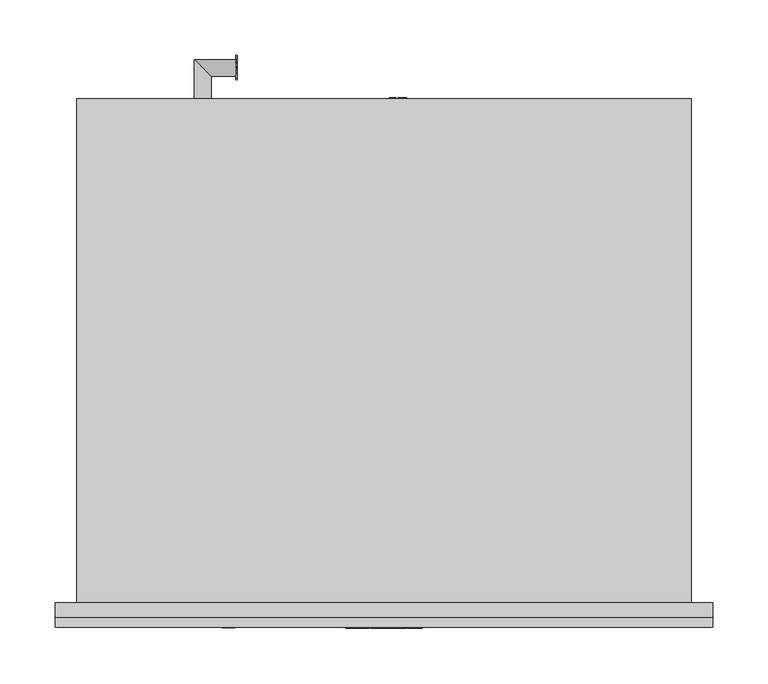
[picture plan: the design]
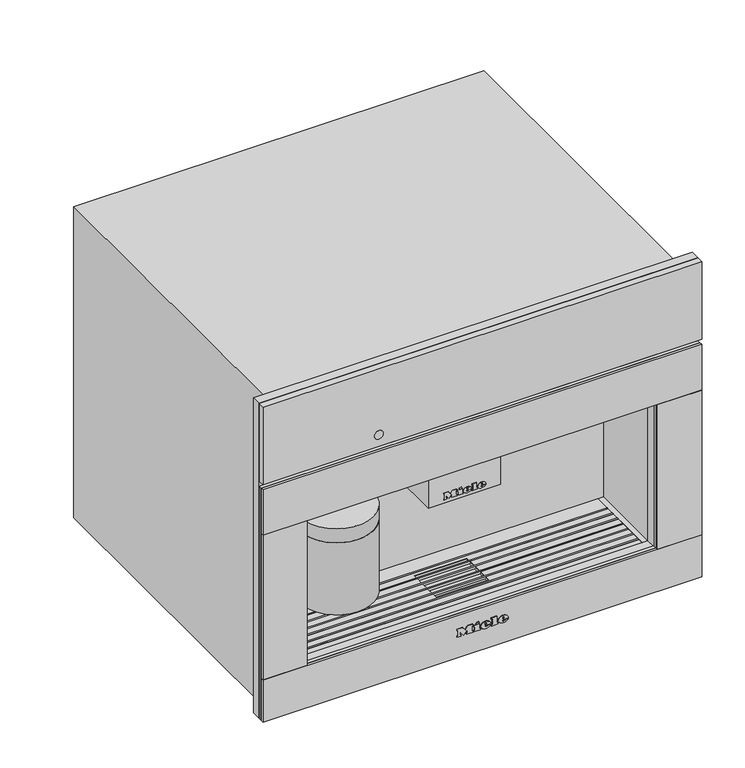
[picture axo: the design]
"""IFC4 building model written with IfcOpenShell, lengths in millimetres: proxy geometry."""

from ifc_helpers import new_model, si_unit, point, frame, frame_2d, origin, place, context, project, spatial, polyline, circle_curve, ellipse_curve, trimmed, segment, composite_curve, outline, extrude, faceted_brep, source, transform, mapped, element, save
from ifc_brep_helpers import plane_surface, cylinder_surface, revolved_surface, extruded_surface, advanced_brep


def specialty_equipment_e3dbea78(model_context):
    return source(origin(), model_context, "Body", "SolidModel", [
        extrude(outline(composite_curve([segment(trimmed(circle_curve(frame_2d((-14.0, 36.5)), 5.0), [point((-9.0, 36.5))], [point((-19.0, 36.5))], False, "CARTESIAN"), True, "CONTINUOUS"), segment(trimmed(circle_curve(frame_2d((-14.0, 36.5)), 5.0), [point((-19.0, 36.5))], [point((-9.0, 36.5))], False, "CARTESIAN"), True, "CONTINUOUS")], self_intersect=False)), frame((0.0, 0.0, 193.0), z_axis=(0.0, 0.0, 1.0), x_axis=(1.0, 0.0, 0.0)), (0.0, 0.0, 1.0), 5.0),
        extrude(outline(composite_curve([segment(trimmed(circle_curve(frame_2d((14.0, 36.5)), 5.0), [point((19.0, 36.5))], [point((9.0, 36.5))], False, "CARTESIAN"), True, "CONTINUOUS"), segment(trimmed(circle_curve(frame_2d((14.0, 36.5)), 5.0), [point((9.0, 36.5))], [point((19.0, 36.5))], False, "CARTESIAN"), True, "CONTINUOUS")], self_intersect=False)), frame((0.0, 0.0, 193.0), z_axis=(0.0, 0.0, 1.0), x_axis=(1.0, 0.0, 0.0)), (0.0, 0.0, 1.0), 5.0),
        extrude(outline(composite_curve([segment(trimmed(circle_curve(frame_2d((-156.5, 49.5)), 50.0), [point((-106.5, 49.5))], [point((-206.5, 49.5))], False, "CARTESIAN"), True, "CONTINUOUS"), segment(trimmed(circle_curve(frame_2d((-156.5, 49.5)), 50.0), [point((-206.5, 49.5))], [point((-106.5, 49.5))], False, "CARTESIAN"), True, "CONTINUOUS")], self_intersect=False)), frame((0.0, 0.0, 100.0), z_axis=(0.0, 0.0, 1.0), x_axis=(1.0, 0.0, 0.0)), (0.0, 0.0, 1.0), 103.0),
        extrude(outline(polyline([(-49.0, 95.0), (49.0, 95.0), (49.0, 20.0), (-49.0, 20.0), (-49.0, 95.0)])), frame((0.0, 0.0, 198.0), z_axis=(0.0, 0.0, 1.0), x_axis=(1.0, 0.0, 0.0)), (0.0, 0.0, 1.0), 75.0),
        extrude(outline(polyline([(455.5, 297.5), (455.5, -297.5), (4.0, -297.5), (4.0, 297.5), (455.5, 297.5)]), holes=[polyline([(273.0, 237.5), (63.0, 237.5), (63.0, -237.5), (273.0, -237.5), (273.0, 237.5)])]), frame((0.0, -13.0, 0.0), z_axis=(0.0, 1.0, 0.0), x_axis=(0.0, 0.0, 1.0)), (0.0, 0.0, 1.0), 13.0),
        extrude(outline(polyline([(473.48348, 22.0), (473.48348, 32.045631), (474.7391839, 32.045631), (474.7391839, 27.128275), (479.8895318, 32.045631), (481.6455552, 32.045631), (477.319263, 27.9155425), (481.8025182, 22.0), (480.267224, 22.0), (476.4289885, 27.0669613), (474.7391839, 25.4531857), (474.7391839, 22.0), (473.48348, 22.0)])), frame((-134.0, 0.0, 0.0), z_axis=(1.0, 0.0, 0.0), x_axis=(0.0, 1.0, 0.0)), (0.0, 0.0, 1.0), 1.0),
        extrude(outline(polyline([(484.5420128, 22.0), (481.8025182, 32.045631), (483.0974628, 32.045631), (484.6867131, 25.4433755), (485.1772224, 23.4053092), (485.7020674, 25.207931), (487.6935352, 32.045631), (489.5599232, 32.045631), (491.0069257, 27.0890343), (492.0835937, 23.4053092), (492.5593878, 25.3845144), (494.1609007, 32.045631), (495.4582979, 32.045631), (492.7212558, 22.0), (491.3772603, 22.0), (488.9664069, 29.7500474), (488.630408, 30.8316204), (488.2527159, 29.5293182), (486.0576866, 22.0), (484.5420128, 22.0)])), frame((-134.0, 0.0, 0.0), z_axis=(1.0, 0.0, 0.0), x_axis=(0.0, 1.0, 0.0)), (0.0, 0.0, 1.0), 1.0),
        advanced_brep(
        [(-156.5, 456.0, 27.0), (-171.5, 456.0, 27.0), (-156.5, 476.5, 27.0), (-171.5, 491.5, 27.0), (-134.0, 476.5, 27.0), (-134.0, 491.5, 27.0)],
        [
            (0, 1, circle_curve(frame((-164.0, 456.0, 27.0), z_axis=(0.0, -1.0, 0.0), x_axis=(-1.0, 0.0, 0.0)), 7.5)),
            (1, 0, circle_curve(frame((-164.0, 456.0, 27.0), z_axis=(0.0, -1.0, 0.0), x_axis=(-1.0, 0.0, 0.0)), 7.5)),
            (0, 2),
            (2, 3, ellipse_curve(frame((-164.0, 484.0, 27.0), z_axis=(-0.707106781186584, -0.7071067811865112, 0.0), x_axis=(0.7071067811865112, -0.7071067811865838, 0.0)), 10.6066017, 7.5)),
            (3, 1),
            (3, 2, ellipse_curve(frame((-164.0, 484.0, 27.0), z_axis=(-0.707106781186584, -0.7071067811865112, 0.0), x_axis=(0.7071067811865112, -0.7071067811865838, 0.0)), 10.6066017, 7.5)),
            (4, 5, circle_curve(frame((-134.0, 484.0, 27.0), z_axis=(1.0, 0.0, 0.0), x_axis=(0.0, 1.0, 0.0)), 7.5)),
            (5, 4, circle_curve(frame((-134.0, 484.0, 27.0), z_axis=(1.0, 0.0, 0.0), x_axis=(0.0, 1.0, 0.0)), 7.5)),
            (2, 4),
            (5, 3),
        ],
        [
            plane_surface(frame((-164.0, 456.0, 27.0), z_axis=(0.0, -1.0, 0.0), x_axis=(0.0, 0.0, 1.0))),
            cylinder_surface(frame((-164.0, 456.0, 27.0), z_axis=(0.0, -1.0, 0.0), x_axis=(-1.0, 0.0, 0.0)), 7.5),
            plane_surface(frame((-134.0, 484.0, 27.0), z_axis=(1.0, 0.0, 0.0), x_axis=(0.0, 0.0, 1.0))),
            cylinder_surface(frame((-164.0, 484.0, 27.0), z_axis=(-1.0, 0.0, 0.0), x_axis=(0.0, 1.0, 0.0)), 7.5),
        ],
        [
            (0, [[1, 2]]),
            (1, [[-1, 3, 4, 5]]),
            (1, [[-2, -5, 6, -3]]),
            (2, [[7, 8]]),
            (3, [[-4, 9, -8, 10]]),
            (3, [[-6, -10, -7, -9]]),
        ],
    ),
        extrude(outline(polyline([(97.0, 20.4012141), (107.045631, 20.4012141), (107.045631, 13.1809168), (105.7899271, 13.1809168), (105.7899271, 19.1455102), (102.8076304, 19.1455102), (102.8076304, 13.4948427), (101.5519266, 13.4948427), (101.5519266, 19.1455102), (98.2557039, 19.1455102), (98.2557039, 13.0239538), (97.0, 13.0239538), (97.0, 20.4012141)])), frame((0.0, 456.0, 0.0), z_axis=(0.0, 1.0, 0.0), x_axis=(0.0, 0.0, 1.0)), (0.0, 0.0, 1.0), 1.0),
        extrude(outline(polyline([(97.0, 11.140398), (107.045631, 11.140398), (107.045631, 9.8846941), (98.2557039, 9.8846941), (98.2557039, 4.8618786), (97.0, 4.8618786), (97.0, 11.140398)])), frame((0.0, 456.0, 0.0), z_axis=(0.0, 1.0, 0.0), x_axis=(0.0, 0.0, 1.0)), (0.0, 0.0, 1.0), 1.0),
        advanced_brep(
        [(55.0, 425.5, 102.0), (55.0, 410.5, 102.0), (20.5239538, 425.5, 102.0), (5.5239538, 410.5, 102.0), (20.5239538, 456.0, 102.0), (5.5239538, 456.0, 102.0)],
        [
            (0, 1, circle_curve(frame((55.0, 418.0, 102.0), z_axis=(1.0, 0.0, 0.0), x_axis=(0.0, -1.0, 0.0)), 7.5)),
            (1, 0, circle_curve(frame((55.0, 418.0, 102.0), z_axis=(1.0, 0.0, 0.0), x_axis=(0.0, -1.0, 0.0)), 7.5)),
            (0, 2),
            (2, 3, ellipse_curve(frame((13.0239538, 418.0, 102.0), z_axis=(0.7071067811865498, -0.7071067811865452, 0.0), x_axis=(0.7071067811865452, 0.7071067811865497, 0.0)), 10.6066017, 7.5)),
            (3, 1),
            (3, 2, ellipse_curve(frame((13.0239538, 418.0, 102.0), z_axis=(0.7071067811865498, -0.7071067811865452, 0.0), x_axis=(0.7071067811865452, 0.7071067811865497, 0.0)), 10.6066017, 7.5)),
            (4, 5, circle_curve(frame((13.0239538, 456.0, 102.0), z_axis=(0.0, 1.0, 0.0), x_axis=(-1.0, 0.0, 0.0)), 7.5)),
            (5, 4, circle_curve(frame((13.0239538, 456.0, 102.0), z_axis=(0.0, 1.0, 0.0), x_axis=(-1.0, 0.0, 0.0)), 7.5)),
            (2, 4),
            (5, 3),
        ],
        [
            plane_surface(frame((55.0, 418.0, 102.0), z_axis=(1.0, 0.0, 0.0), x_axis=(0.0, 0.0, 1.0))),
            cylinder_surface(frame((55.0, 418.0, 102.0), z_axis=(1.0, 0.0, 0.0), x_axis=(0.0, -1.0, 0.0)), 7.5),
            plane_surface(frame((13.0239538, 456.0, 102.0), z_axis=(0.0, 1.0, 0.0), x_axis=(0.0, 0.0, 1.0))),
            cylinder_surface(frame((13.0239538, 418.0, 102.0), z_axis=(0.0, -1.0, 0.0), x_axis=(-1.0, 0.0, 0.0)), 7.5),
        ],
        [
            (0, [[1, 2]]),
            (1, [[-1, 3, 4, 5]]),
            (1, [[-2, -5, 6, -3]]),
            (2, [[7, 8]]),
            (3, [[-4, 9, -8, 10]]),
            (3, [[-6, -10, -7, -9]]),
        ],
    ),
        advanced_brep(
        [(-110.0, 49.5, 252.0), (-203.0, 49.5, 252.0), (-206.5, 49.5, 223.5), (-106.5, 49.5, 223.5), (-110.0, 49.5, 273.0), (-203.0, 49.5, 273.0), (-156.5, 49.5, 273.0), (-106.5, 49.5, 203.0), (-206.5, 49.5, 203.0), (-156.5, 49.5, 203.0)],
        [
            (0, 1, circle_curve(frame((-156.5, 49.5, 252.0), z_axis=(0.0, 0.0, -1.0), x_axis=(-1.0, 0.0, 0.0)), 46.5)),
            (1, 2, circle_curve(frame((-206.7961166, 49.5, 238.0012775), z_axis=(0.0, 1.0, 0.0), x_axis=(-1.0, 0.0, 0.0)), 14.5043005)),
            (2, 3, circle_curve(frame((-156.5, 49.5, 223.5), z_axis=(0.0, 0.0, 1.0), x_axis=(-1.0, 0.0, 0.0)), 50.0)),
            (3, 0, circle_curve(frame((-106.2038834, 49.5, 238.0012775), z_axis=(0.0, 1.0, 0.0), x_axis=(1.0, 0.0, 0.0)), 14.5043005)),
            (4, 5, circle_curve(frame((-156.5, 49.5, 273.0), z_axis=(0.0, 0.0, -1.0), x_axis=(-1.0, 0.0, 0.0)), 46.5)),
            (5, 1),
            (0, 4),
            (6, 4),
            (4, 5, circle_curve(frame((-156.5, 49.5, 273.0), z_axis=(0.0, 0.0, 1.0), x_axis=(-1.0, 0.0, 0.0)), 46.5)),
            (5, 6),
            (7, 8, circle_curve(frame((-156.5, 49.5, 203.0), z_axis=(0.0, 0.0, -1.0), x_axis=(-1.0, 0.0, 0.0)), 50.0)),
            (8, 9),
            (9, 7),
            (8, 7, circle_curve(frame((-156.5, 49.5, 203.0), z_axis=(0.0, 0.0, -1.0), x_axis=(-1.0, 0.0, 0.0)), 50.0)),
            (2, 8),
            (7, 3),
            (2, 3, circle_curve(frame((-156.5, 49.5, 223.5), z_axis=(0.0, 0.0, -1.0), x_axis=(-1.0, 0.0, 0.0)), 50.0)),
            (1, 0, circle_curve(frame((-156.5, 49.5, 252.0), z_axis=(0.0, 0.0, -1.0), x_axis=(-1.0, 0.0, 0.0)), 46.5)),
        ],
        [
            revolved_surface(trimmed(ellipse_curve(frame((-206.7961166, 49.5, 238.0012775), z_axis=(0.0, -1.0, 0.0), x_axis=(-1.0, 0.0, 0.0)), 14.5043005, 14.5043005), [point((-206.5, 49.5, 223.5))], [point((-203.0, 49.5, 252.0))], True, "CARTESIAN"), (-156.5, 49.5, 388.7361736), (0.0, 0.0, 1.0)),
            cylinder_surface(frame((-156.5, 49.5, 388.7361736), z_axis=(0.0, 0.0, 1.0), x_axis=(-1.0, 0.0, 0.0)), 46.5),
            plane_surface(frame((-156.5, 49.5, 273.0), z_axis=(0.0, 0.0, 1.0), x_axis=(-1.0, 0.0, 0.0))),
            plane_surface(frame((-156.5, 49.5, 203.0), z_axis=(0.0, 0.0, -1.0), x_axis=(-1.0, 0.0, 0.0))),
            cylinder_surface(frame((-156.5, 49.5, 388.7361736), z_axis=(0.0, 0.0, 1.0), x_axis=(-1.0, 0.0, 0.0)), 50.0),
        ],
        [
            (0, [[1, 2, 3, 4]]),
            (1, [[5, 6, -1, 7]]),
            (2, [[8, 9, 10]]),
            (3, [[11, 12, 13]]),
            (3, [[14, -13, -12]]),
            (4, [[-3, 15, -11, 16]]),
            (4, [[17, -16, -14, -15]]),
            (0, [[18, -4, -17, -2]]),
            (1, [[-9, -7, -18, -6]]),
            (2, [[-10, -5, -8]]),
        ],
    ),
        faceted_brep([(229.5, 82.0925571, 60.0), (229.5, 80.0925571, 60.0), (-229.5, 80.0925571, 60.0), (-229.5, 82.0925571, 60.0), (229.5, 70.0550731, 60.0), (229.5, 68.0550731, 60.0), (-229.5, 68.0550731, 60.0), (-229.5, 70.0550731, 60.0), (229.5, 58.0175891, 60.0), (229.5, 56.0175891, 60.0), (-229.5, 56.0175891, 60.0), (-229.5, 58.0175891, 60.0), (229.5, 45.9801052, 60.0), (229.5, 43.9801052, 60.0), (-229.5, 43.9801052, 60.0), (-229.5, 45.9801052, 60.0), (229.5, 33.9426212, 60.0), (229.5, 31.9426212, 60.0), (-229.5, 31.9426212, 60.0), (-229.5, 33.9426212, 60.0), (229.5, 21.9776522, 60.0), (229.5, 19.9776522, 60.0), (-229.5, 19.9776522, 60.0), (-229.5, 21.9776522, 60.0), (229.5, 10.0, 60.0), (229.5, 8.0, 60.0), (-229.5, 8.0, 60.0), (-229.5, 10.0, 60.0), (-229.5, 45.9801052, 62.0), (-36.0, 45.9801052, 62.0), (-36.0, 45.9801052, 63.0), (-229.5, 45.9801052, 63.0), (-229.5, 45.9801052, 63.5), (229.5, 45.9801052, 63.5), (229.5, 45.9801052, 63.0), (36.0, 45.9801052, 63.0), (36.0, 45.9801052, 62.0), (229.5, 45.9801052, 62.0), (229.5, 19.9776522, 62.0), (229.5, 10.0, 62.0), (-229.5, 10.0, 62.0), (-229.5, 19.9776522, 62.0), (229.5, 43.9801052, 62.0), (229.5, 33.9426212, 62.0), (36.0, 33.9426212, 62.0), (36.0, 43.9801052, 62.0), (229.5, 56.0175891, 62.0), (36.0, 56.0175891, 62.0), (229.5, 68.0550731, 62.0), (229.5, 58.0175891, 62.0), (36.0, 58.0175891, 62.0), (36.0, 68.0550731, 62.0), (-229.5, 33.9426212, 62.0), (-229.5, 43.9801052, 62.0), (-36.0, 43.9801052, 62.0), (-36.0, 33.9426212, 62.0), (-229.5, 56.0175891, 62.0), (-36.0, 56.0175891, 62.0), (-229.5, 58.0175891, 62.0), (-229.5, 68.0550731, 62.0), (-36.0, 68.0550731, 62.0), (-36.0, 58.0175891, 62.0), (-229.5, 104.5, 62.0), (229.5, 104.5, 62.0), (229.5, 82.0925571, 62.0), (-229.5, 82.0925571, 62.0), (36.0, 76.0, 62.0), (-36.0, 76.0, 62.0), (-36.0, 70.0550731, 62.0), (-229.5, 70.0550731, 62.0), (-229.5, 80.0925571, 62.0), (229.5, 80.0925571, 62.0), (229.5, 70.0550731, 62.0), (36.0, 70.0550731, 62.0), (229.5, 0.0, 62.0), (-229.5, 0.0, 62.0), (-229.5, 8.0, 62.0), (229.5, 8.0, 62.0), (-36.0, 25.0, 62.0), (36.0, 25.0, 62.0), (36.0, 31.9426212, 62.0), (229.5, 31.9426212, 62.0), (229.5, 21.9776522, 62.0), (-229.5, 21.9776522, 62.0), (-229.5, 31.9426212, 62.0), (-36.0, 31.9426212, 62.0), (229.5, 104.5, 63.0), (-229.5, 104.5, 63.0), (-229.5, 82.0925571, 63.0), (229.5, 82.0925571, 63.0), (-229.5, 0.0, 63.0), (229.5, 0.0, 63.0), (229.5, 8.0, 63.0), (-229.5, 8.0, 63.0), (-36.0, 76.0, 63.0), (36.0, 76.0, 63.0), (36.0, 70.0550731, 63.0), (229.5, 70.0550731, 63.0), (229.5, 80.0925571, 63.0), (-229.5, 80.0925571, 63.0), (-229.5, 70.0550731, 63.0), (-36.0, 70.0550731, 63.0), (36.0, 25.0, 63.0), (-36.0, 25.0, 63.0), (-36.0, 31.9426212, 63.0), (-229.5, 31.9426212, 63.0), (-229.5, 21.9776522, 63.0), (229.5, 21.9776522, 63.0), (229.5, 31.9426212, 63.0), (36.0, 31.9426212, 63.0), (-229.5, 19.9776522, 63.0), (-229.5, 10.0, 63.0), (229.5, 10.0, 63.0), (229.5, 19.9776522, 63.0), (-229.5, 43.9801052, 63.0), (-229.5, 33.9426212, 63.0), (-36.0, 33.9426212, 63.0), (-36.0, 43.9801052, 63.0), (-229.5, 56.0175891, 63.0), (-36.0, 56.0175891, 63.0), (-229.5, 68.0550731, 63.0), (-229.5, 58.0175891, 63.0), (-36.0, 58.0175891, 63.0), (-36.0, 68.0550731, 63.0), (229.5, 33.9426212, 63.0), (229.5, 43.9801052, 63.0), (36.0, 43.9801052, 63.0), (36.0, 33.9426212, 63.0), (229.5, 56.0175891, 63.0), (36.0, 56.0175891, 63.0), (229.5, 58.0175891, 63.0), (229.5, 68.0550731, 63.0), (36.0, 68.0550731, 63.0), (36.0, 58.0175891, 63.0), (-229.5, 8.0, 63.5), (-229.5, 10.0, 63.5), (-229.5, 19.9776522, 63.5), (-229.5, 21.9776522, 63.5), (-229.5, 31.9426212, 63.5), (-229.5, 33.9426212, 63.5), (-229.5, 43.9801052, 63.5), (-229.5, 56.0175891, 63.5), (-229.5, 58.0175891, 63.5), (-229.5, 68.0550731, 63.5), (-229.5, 70.0550731, 63.5), (-229.5, 80.0925571, 63.5), (-229.5, 82.0925571, 63.5), (229.5, 82.0925571, 63.5), (229.5, 80.0925571, 63.5), (229.5, 70.0550731, 63.5), (229.5, 68.0550731, 63.5), (229.5, 58.0175891, 63.5), (229.5, 56.0175891, 63.5), (229.5, 43.9801052, 63.5), (229.5, 33.9426212, 63.5), (229.5, 31.9426212, 63.5), (229.5, 21.9776522, 63.5), (229.5, 19.9776522, 63.5), (229.5, 10.0, 63.5), (229.5, 8.0, 63.5)], [[[0, 1, 2, 3]], [[4, 5, 6, 7]], [[8, 9, 10, 11]], [[12, 13, 14, 15]], [[16, 17, 18, 19]], [[20, 21, 22, 23]], [[24, 25, 26, 27]], [[12, 15, 28, 29, 30, 31, 32, 33, 34, 35, 36, 37]], [[38, 39, 40, 41]], [[42, 43, 44, 45]], [[46, 37, 36, 47]], [[48, 49, 50, 51]], [[52, 53, 54, 55]], [[28, 56, 57, 29]], [[58, 59, 60, 61]], [[62, 63, 64, 65]], [[66, 67, 68, 69, 70, 71, 72, 73]], [[74, 75, 76, 77]], [[78, 79, 80, 81, 82, 83, 84, 85]], [[86, 87, 88, 89]], [[90, 91, 92, 93]], [[94, 95, 96, 97, 98, 99, 100, 101]], [[102, 103, 104, 105, 106, 107, 108, 109]], [[110, 111, 112, 113]], [[114, 115, 116, 117]], [[118, 31, 30, 119]], [[120, 121, 122, 123]], [[124, 125, 126, 127]], [[34, 128, 129, 35]], [[130, 131, 132, 133]], [[63, 62, 87, 86]], [[87, 62, 65, 3, 2, 70, 69, 7, 6, 59, 58, 11, 10, 56, 28, 15, 14, 53, 52, 19, 18, 84, 83, 23, 22, 41, 40, 27, 26, 76, 75, 90, 93, 134, 135, 111, 110, 136, 137, 106, 105, 138, 139, 115, 114, 140, 32, 31, 118, 141, 142, 121, 120, 143, 144, 100, 99, 145, 146, 88]], [[75, 74, 91, 90]], [[63, 86, 89, 147, 148, 98, 97, 149, 150, 131, 130, 151, 152, 128, 34, 33, 153, 125, 124, 154, 155, 108, 107, 156, 157, 113, 112, 158, 159, 92, 91, 74, 77, 25, 24, 39, 38, 21, 20, 82, 81, 17, 16, 43, 42, 13, 12, 37, 46, 9, 8, 49, 48, 5, 4, 72, 71, 1, 0, 64]], [[66, 95, 94, 67]], [[55, 54, 117, 116]], [[29, 57, 119, 30]], [[61, 60, 123, 122]], [[67, 94, 101, 68]], [[103, 78, 85, 104]], [[78, 103, 102, 79]], [[45, 44, 127, 126]], [[47, 36, 35, 129]], [[51, 50, 133, 132]], [[95, 66, 73, 96]], [[79, 102, 109, 80]], [[158, 135, 134, 159]], [[156, 137, 136, 157]], [[154, 139, 138, 155]], [[33, 32, 140, 153]], [[151, 142, 141, 152]], [[149, 144, 143, 150]], [[147, 146, 145, 148]], [[24, 27, 40, 39]], [[135, 158, 112, 111]], [[26, 25, 77, 76]], [[159, 134, 93, 92]], [[20, 23, 83, 82]], [[137, 156, 107, 106]], [[22, 21, 38, 41]], [[157, 136, 110, 113]], [[16, 19, 52, 55, 116, 115, 139, 154, 124, 127, 44, 43]], [[18, 17, 81, 80, 109, 108, 155, 138, 105, 104, 85, 84]], [[14, 13, 42, 45, 126, 125, 153, 140, 114, 117, 54, 53]], [[8, 11, 58, 61, 122, 121, 142, 151, 130, 133, 50, 49]], [[10, 9, 46, 47, 129, 128, 152, 141, 118, 119, 57, 56]], [[4, 7, 69, 68, 101, 100, 144, 149, 97, 96, 73, 72]], [[6, 5, 48, 51, 132, 131, 150, 143, 120, 123, 60, 59]], [[0, 3, 65, 64]], [[146, 147, 89, 88]], [[2, 1, 71, 70]], [[148, 145, 99, 98]]]),
        faceted_brep([(-278.0, 456.0, 0.0), (-278.0, 0.0, 0.0), (-278.0, 0.0, 446.0), (-278.0, 456.0, 446.0), (278.0, 456.0, 0.0), (278.0, 456.0, 446.0), (278.0, 0.0, 446.0), (278.0, 0.0, 0.0), (55.0, 456.0, 133.0), (-22.0, 456.0, 133.0), (-22.0, 456.0, 89.0), (35.0, 456.0, 66.0), (55.0, 456.0, 66.0), (-36.0, 76.0, 58.0), (36.0, 76.0, 58.0), (36.0, 76.0, 62.0), (-36.0, 76.0, 62.0), (36.0, 25.0, 58.0), (-36.0, 25.0, 58.0), (-36.0, 25.0, 62.0), (36.0, 25.0, 62.0), (237.5, 0.0, 273.0), (237.5, 0.0, 63.0), (229.5, 0.0, 63.0), (229.5, 0.0, 62.0), (-229.5, 0.0, 62.0), (-229.5, 0.0, 63.0), (-237.5, 0.0, 63.0), (-237.5, 0.0, 273.0), (237.5, 104.5, 273.0), (-237.5, 104.5, 273.0), (-237.5, 104.5, 63.0), (-229.5, 104.5, 63.0), (-229.5, 104.5, 62.0), (229.5, 104.5, 62.0), (229.5, 104.5, 63.0), (237.5, 104.5, 63.0), (-22.0, 400.0, 133.0), (55.0, 400.0, 133.0), (55.0, 400.0, 66.0), (35.0, 400.0, 66.0), (-22.0, 400.0, 89.0)], [[[0, 1, 2, 3]], [[4, 5, 6, 7]], [[0, 3, 5, 4], [8, 9, 10, 11, 12]], [[13, 14, 15, 16]], [[17, 18, 19, 20]], [[3, 2, 6, 5]], [[2, 1, 7, 6], [21, 22, 23, 24, 25, 26, 27, 28]], [[1, 0, 4, 7]], [[29, 30, 31, 32, 33, 34, 35, 36]], [[29, 36, 22, 21]], [[22, 36, 35, 23]], [[31, 27, 26, 32]], [[31, 30, 28, 27]], [[30, 29, 21, 28]], [[34, 33, 25, 24], [16, 15, 20, 19]], [[25, 33, 32, 26]], [[34, 24, 23, 35]], [[14, 13, 18, 17]], [[18, 13, 16, 19]], [[14, 17, 20, 15]], [[37, 38, 39, 40, 41]], [[38, 37, 9, 8]], [[39, 38, 8, 12]], [[40, 39, 12, 11]], [[41, 40, 11, 10]], [[37, 41, 10, 9]]]),
        advanced_brep(
        [(27.088, -23.0, 36.7018), (27.088, -23.0, 37.8532), (34.7146, -23.0, 37.8532), (21.445, -23.0, 37.8532), (24.58, -23.0, 34.0), (34.5208, -23.0, 36.7018), (31.078, -23.0, 36.7018), (28.3648, -23.0, 35.425), (27.088, -23.0, 39.3124), (27.088, -23.0, 40.555), (29.0374, -23.0, 40.555), (29.0374, -23.0, 39.3124), (27.088, -22.0, 36.7018), (28.3648, -22.0, 35.425), (31.078, -22.0, 36.7018), (34.5208, -22.0, 36.7018), (24.58, -22.0, 34.0), (21.445, -22.0, 37.8532), (34.7146, -22.0, 37.8532), (27.088, -22.0, 37.8532), (27.088, -22.0, 39.3124), (29.0374, -22.0, 39.3124), (29.0374, -22.0, 40.555), (27.088, -22.0, 40.555)],
        [
            (0, 1),
            (1, 2),
            (2, 3, ellipse_curve(frame((28.0798, -23.0, 37.8532), z_axis=(0.0, -1.0, 0.0), x_axis=(-1.0, 0.0, 0.0)), 6.6348, 5.4834)),
            (3, 4, circle_curve(frame((25.8568622, -23.0, 38.2408), z_axis=(0.0, -1.0, 0.0), x_axis=(0.0, 0.0, -1.0)), 4.4288556)),
            (4, 5, circle_curve(frame((27.9469808, -23.0, 41.2504), z_axis=(0.0, -1.0, 0.0), x_axis=(0.0, 0.0, -1.0)), 7.9940516)),
            (5, 6),
            (6, 7, circle_curve(frame((28.9220588, -23.0, 37.762), z_axis=(0.0, 1.0, 0.0), x_axis=(0.0, 0.0, -1.0)), 2.4025208)),
            (7, 0, circle_curve(frame((28.3648, -23.0, 36.7018), z_axis=(0.0, 1.0, 0.0), x_axis=(0.0, 0.0, -1.0)), 1.2768)),
            (8, 9),
            (9, 10, circle_curve(frame((28.0627, -23.0, 40.555), z_axis=(0.0, 1.0, 0.0), x_axis=(0.0, 0.0, -1.0)), 0.9747)),
            (10, 11),
            (11, 8),
            (12, 13, circle_curve(frame((28.3648, -22.0, 36.7018), z_axis=(0.0, -1.0, 0.0), x_axis=(0.0, 0.0, -1.0)), 1.2768)),
            (13, 14, circle_curve(frame((28.9220588, -22.0, 37.762), z_axis=(0.0, -1.0, 0.0), x_axis=(0.0, 0.0, -1.0)), 2.4025208)),
            (14, 15),
            (15, 16, circle_curve(frame((27.9469808, -22.0, 41.2504), z_axis=(0.0, 1.0, 0.0), x_axis=(0.0, 0.0, -1.0)), 7.9940516)),
            (16, 17, circle_curve(frame((25.8568622, -22.0, 38.2408), z_axis=(0.0, 1.0, 0.0), x_axis=(0.0, 0.0, -1.0)), 4.4288556)),
            (17, 18, ellipse_curve(frame((28.0798, -22.0, 37.8532), z_axis=(0.0, 1.0, 0.0), x_axis=(-1.0, 0.0, 0.0)), 6.6348, 5.4834)),
            (18, 19),
            (19, 12),
            (20, 21),
            (21, 22),
            (22, 23, circle_curve(frame((28.0627, -22.0, 40.555), z_axis=(0.0, -1.0, 0.0), x_axis=(0.0, 0.0, -1.0)), 0.9747)),
            (23, 20),
            (0, 12),
            (19, 1),
            (18, 2),
            (5, 15),
            (14, 6),
            (17, 3),
            (13, 7),
            (16, 4),
            (8, 20),
            (23, 9),
            (22, 10),
            (21, 11),
        ],
        [
            plane_surface(frame((27.088, -23.0, 37.8532), z_axis=(0.0, -1.0, 0.0), x_axis=(0.0, 0.0, 1.0))),
            plane_surface(frame((27.088, -22.0, 37.8532), z_axis=(0.0, 1.0, 0.0), x_axis=(0.0, 0.0, -1.0))),
            plane_surface(frame((27.088, -23.0, 36.7018), z_axis=(1.0, 0.0, 0.0), x_axis=(0.0, 1.0, 0.0))),
            plane_surface(frame((27.088, -23.0, 37.8532), z_axis=(0.0, 0.0, -1.0), x_axis=(0.0, 1.0, 0.0))),
            plane_surface(frame((34.5208, -23.0, 36.7018), z_axis=(0.0, 0.0, 1.0), x_axis=(0.0, 1.0, 0.0))),
            extruded_surface(trimmed(ellipse_curve(frame((28.0798, -21.0, 37.8532), z_axis=(0.0, -1.0, 0.0), x_axis=(-1.0, 0.0, 0.0)), 6.6348, 5.4834), [point((34.7146, -21.0, 37.8532))], [point((21.445, -21.0, 37.8532))], True, "CARTESIAN"), (0.0, -1.0, 0.0), 1.0),
            revolved_surface(polyline([(28.9220588, -22.0, 35.3594792), (28.9220588, -23.0, 35.3594792)]), (28.9220588, -22.0, 37.762), (0.0, 1.0, 0.0)),
            revolved_surface(polyline([(28.3648, -22.0, 35.425), (28.3648, -23.0, 35.425)]), (28.3648, -22.0, 36.7018), (0.0, 1.0, 0.0)),
            cylinder_surface(frame((25.8568622, -22.0, 38.2408), z_axis=(0.0, -1.0, 0.0), x_axis=(0.0, 0.0, -1.0)), 4.4288556),
            cylinder_surface(frame((27.9469808, -22.0, 41.2504), z_axis=(0.0, -1.0, 0.0), x_axis=(0.0, 0.0, -1.0)), 7.9940516),
            plane_surface(frame((27.088, -23.0, 39.3124), z_axis=(1.0, 0.0, 0.0), x_axis=(0.0, 1.0, 0.0))),
            revolved_surface(polyline([(28.0627, -22.0, 39.5803), (28.0627, -23.0, 39.5803)]), (28.0627, -22.0, 40.555), (0.0, 1.0, 0.0)),
            plane_surface(frame((29.0374, -23.0, 40.555), z_axis=(-1.0, 0.0, 0.0), x_axis=(0.0, 1.0, 0.0))),
            plane_surface(frame((29.0374, -23.0, 39.3124), z_axis=(0.0, 0.0, 1.0), x_axis=(0.0, 1.0, 0.0))),
        ],
        [
            (0, [[1, 2, 3, 4, 5, 6, 7, 8], [9, 10, 11, 12]]),
            (1, [[13, 14, 15, 16, 17, 18, 19, 20], [21, 22, 23, 24]]),
            (2, [[-1, 25, -20, 26]]),
            (3, [[-2, -26, -19, 27]]),
            (4, [[-6, 28, -15, 29]]),
            (5, [[-3, -27, -18, 30]]),
            (6, [[-7, -29, -14, 31]]),
            (7, [[-8, -31, -13, -25]]),
            (8, [[-4, -30, -17, 32]]),
            (9, [[-5, -32, -16, -28]]),
            (10, [[-9, 33, -24, 34]]),
            (11, [[-10, -34, -23, 35]]),
            (12, [[-11, -35, -22, 36]]),
            (13, [[-12, -36, -21, -33]]),
        ],
    ),
        advanced_brep(
        [(3.2962, -23.0, 36.7018), (3.2962, -23.0, 37.8532), (10.9228, -23.0, 37.8532), (-2.3468, -23.0, 37.8532), (0.7882, -23.0, 34.0), (10.729, -23.0, 36.7018), (7.2862, -23.0, 36.7018), (4.573, -23.0, 35.425), (3.2962, -23.0, 39.3124), (3.2962, -23.0, 40.555), (5.2456, -23.0, 40.555), (5.2456, -23.0, 39.3124), (3.2962, -22.0, 36.7018), (4.573, -22.0, 35.425), (7.2862, -22.0, 36.7018), (10.729, -22.0, 36.7018), (0.7882, -22.0, 34.0), (-2.3468, -22.0, 37.8532), (10.9228, -22.0, 37.8532), (3.2962, -22.0, 37.8532), (3.2962, -22.0, 39.3124), (5.2456, -22.0, 39.3124), (5.2456, -22.0, 40.555), (3.2962, -22.0, 40.555)],
        [
            (0, 1),
            (1, 2),
            (2, 3, ellipse_curve(frame((4.288, -23.0, 37.8532), z_axis=(0.0, -1.0, 0.0), x_axis=(-1.0, 0.0, 0.0)), 6.6348, 5.4834)),
            (3, 4, circle_curve(frame((2.0650622, -23.0, 38.2408), z_axis=(0.0, -1.0, 0.0), x_axis=(0.0, 0.0, -1.0)), 4.4288556)),
            (4, 5, circle_curve(frame((4.1551808, -23.0, 41.2504), z_axis=(0.0, -1.0, 0.0), x_axis=(0.0, 0.0, -1.0)), 7.9940516)),
            (5, 6),
            (6, 7, circle_curve(frame((5.1302588, -23.0, 37.762), z_axis=(0.0, 1.0, 0.0), x_axis=(0.0, 0.0, -1.0)), 2.4025208)),
            (7, 0, circle_curve(frame((4.573, -23.0, 36.7018), z_axis=(0.0, 1.0, 0.0), x_axis=(0.0, 0.0, -1.0)), 1.2768)),
            (8, 9),
            (9, 10, circle_curve(frame((4.2709, -23.0, 40.555), z_axis=(0.0, 1.0, 0.0), x_axis=(0.0, 0.0, -1.0)), 0.9747)),
            (10, 11),
            (11, 8),
            (12, 13, circle_curve(frame((4.573, -22.0, 36.7018), z_axis=(0.0, -1.0, 0.0), x_axis=(0.0, 0.0, -1.0)), 1.2768)),
            (13, 14, circle_curve(frame((5.1302588, -22.0, 37.762), z_axis=(0.0, -1.0, 0.0), x_axis=(0.0, 0.0, -1.0)), 2.4025208)),
            (14, 15),
            (15, 16, circle_curve(frame((4.1551808, -22.0, 41.2504), z_axis=(0.0, 1.0, 0.0), x_axis=(0.0, 0.0, -1.0)), 7.9940516)),
            (16, 17, circle_curve(frame((2.0650622, -22.0, 38.2408), z_axis=(0.0, 1.0, 0.0), x_axis=(0.0, 0.0, -1.0)), 4.4288556)),
            (17, 18, ellipse_curve(frame((4.288, -22.0, 37.8532), z_axis=(0.0, 1.0, 0.0), x_axis=(-1.0, 0.0, 0.0)), 6.6348, 5.4834)),
            (18, 19),
            (19, 12),
            (20, 21),
            (21, 22),
            (22, 23, circle_curve(frame((4.2709, -22.0, 40.555), z_axis=(0.0, -1.0, 0.0), x_axis=(0.0, 0.0, -1.0)), 0.9747)),
            (23, 20),
            (0, 12),
            (19, 1),
            (18, 2),
            (5, 15),
            (14, 6),
            (17, 3),
            (13, 7),
            (16, 4),
            (8, 20),
            (23, 9),
            (22, 10),
            (21, 11),
        ],
        [
            plane_surface(frame((3.2962, -23.0, 37.8532), z_axis=(0.0, -1.0, 0.0), x_axis=(0.0, 0.0, 1.0))),
            plane_surface(frame((3.2962, -22.0, 37.8532), z_axis=(0.0, 1.0, 0.0), x_axis=(0.0, 0.0, -1.0))),
            plane_surface(frame((3.2962, -23.0, 36.7018), z_axis=(1.0, 0.0, 0.0), x_axis=(0.0, 1.0, 0.0))),
            plane_surface(frame((3.2962, -23.0, 37.8532), z_axis=(0.0, 0.0, -1.0), x_axis=(0.0, 1.0, 0.0))),
            plane_surface(frame((10.729, -23.0, 36.7018), z_axis=(0.0, 0.0, 1.0), x_axis=(0.0, 1.0, 0.0))),
            extruded_surface(trimmed(ellipse_curve(frame((4.288, -21.0, 37.8532), z_axis=(0.0, -1.0, 0.0), x_axis=(-1.0, 0.0, 0.0)), 6.6348, 5.4834), [point((10.9228, -21.0, 37.8532))], [point((-2.3468, -21.0, 37.8532))], True, "CARTESIAN"), (0.0, -1.0, 0.0), 1.0),
            revolved_surface(polyline([(5.1302588, -22.0, 35.3594792), (5.1302588, -23.0, 35.3594792)]), (5.1302588, -22.0, 37.762), (0.0, 1.0, 0.0)),
            revolved_surface(polyline([(4.573, -22.0, 35.425), (4.573, -23.0, 35.425)]), (4.573, -22.0, 36.7018), (0.0, 1.0, 0.0)),
            cylinder_surface(frame((2.0650622, -22.0, 38.2408), z_axis=(0.0, -1.0, 0.0), x_axis=(0.0, 0.0, -1.0)), 4.4288556),
            cylinder_surface(frame((4.1551808, -22.0, 41.2504), z_axis=(0.0, -1.0, 0.0), x_axis=(0.0, 0.0, -1.0)), 7.9940516),
            plane_surface(frame((3.2962, -23.0, 39.3124), z_axis=(1.0, 0.0, 0.0), x_axis=(0.0, 1.0, 0.0))),
            revolved_surface(polyline([(4.2709, -22.0, 39.5803), (4.2709, -23.0, 39.5803)]), (4.2709, -22.0, 40.555), (0.0, 1.0, 0.0)),
            plane_surface(frame((5.2456, -23.0, 40.555), z_axis=(-1.0, 0.0, 0.0), x_axis=(0.0, 1.0, 0.0))),
            plane_surface(frame((5.2456, -23.0, 39.3124), z_axis=(0.0, 0.0, 1.0), x_axis=(0.0, 1.0, 0.0))),
        ],
        [
            (0, [[1, 2, 3, 4, 5, 6, 7, 8], [9, 10, 11, 12]]),
            (1, [[13, 14, 15, 16, 17, 18, 19, 20], [21, 22, 23, 24]]),
            (2, [[-1, 25, -20, 26]]),
            (3, [[-2, -26, -19, 27]]),
            (4, [[-6, 28, -15, 29]]),
            (5, [[-3, -27, -18, 30]]),
            (6, [[-7, -29, -14, 31]]),
            (7, [[-8, -31, -13, -25]]),
            (8, [[-4, -30, -17, 32]]),
            (9, [[-5, -32, -16, -28]]),
            (10, [[-9, 33, -24, 34]]),
            (11, [[-10, -34, -23, 35]]),
            (12, [[-11, -35, -22, 36]]),
            (13, [[-12, -36, -21, -33]]),
        ],
    ),
        extrude(outline(polyline([(44.7274, -9.164), (42.8806, -8.2976), (44.6818, -4.433), (46.5286, -5.288), (44.7274, -9.164)])), frame((0.0, -23.0, 0.0), z_axis=(0.0, 1.0, 0.0), x_axis=(0.0, 0.0, 1.0)), (0.0, 0.0, 1.0), 1.0),
        extrude(outline(polyline([(42.6298, -11.9798), (40.5892, -11.9798), (40.5892, -10.6232), (35.9152, -10.6232), (35.9152, -11.9798), (34.0, -11.9798), (34.0, -2.9852), (35.9152, -2.9852), (35.9152, -4.3076), (42.6298, -4.3076), (42.6298, -11.9798)])), frame((0.0, -23.0, 0.0), z_axis=(0.0, 1.0, 0.0), x_axis=(0.0, 0.0, 1.0)), (0.0, 0.0, 1.0), 1.0),
        extrude(outline(polyline([(43.5418, 11.5612), (43.5418, 12.9292), (35.9152, 12.9292), (35.9152, 11.5612), (34.0, 11.5612), (34.0, 20.8066), (35.9152, 20.8066), (35.9152, 19.4044), (45.4, 19.4044), (45.4, 11.5612), (43.5418, 11.5612)])), frame((0.0, -23.0, 0.0), z_axis=(0.0, 1.0, 0.0), x_axis=(0.0, 0.0, 1.0)), (0.0, 0.0, 1.0), 1.0),
        extrude(outline(polyline([(43.5418, -34.7), (43.5418, -33.3206), (35.9152, -33.3206), (35.9152, -34.7), (34.0, -34.7), (34.0, -29.684), (35.9152, -29.684), (35.9152, -31.052), (40.7429247, -31.052), (34.0, -25.9562), (40.9402223, -20.8376), (35.9152, -20.8376), (35.9152, -22.2398), (34.0, -22.2398), (34.0, -13.1426), (35.9152, -13.1426), (35.9152, -14.5904), (43.5418, -14.5904), (43.5418, -13.1426), (45.4, -13.1426), (45.4, -20.0852), (41.125, -23.414), (45.4, -26.7542), (45.4, -34.7), (43.5418, -34.7)])), frame((0.0, -23.0, 0.0), z_axis=(0.0, 1.0, 0.0), x_axis=(0.0, 0.0, 1.0)), (0.0, 0.0, 1.0), 1.0),
        advanced_brep(
        [(22.348, 19.0, 205.5278), (22.348, 19.0, 206.4772), (28.6366, 19.0, 206.4772), (17.695, 19.0, 206.4772), (20.28, 19.0, 203.3), (28.4768, 19.0, 205.5278), (25.638, 19.0, 205.5278), (23.4008, 19.0, 204.475), (22.348, 19.0, 207.6804), (22.348, 19.0, 208.705), (23.9554, 19.0, 208.705), (23.9554, 19.0, 207.6804), (22.348, 20.0, 205.5278), (23.4008, 20.0, 204.475), (25.638, 20.0, 205.5278), (28.4768, 20.0, 205.5278), (20.28, 20.0, 203.3), (17.695, 20.0, 206.4772), (28.6366, 20.0, 206.4772), (22.348, 20.0, 206.4772), (22.348, 20.0, 207.6804), (23.9554, 20.0, 207.6804), (23.9554, 20.0, 208.705), (22.348, 20.0, 208.705)],
        [
            (0, 1),
            (1, 2),
            (2, 3, ellipse_curve(frame((23.1658, 19.0, 206.4772), z_axis=(0.0, -1.0, 0.0), x_axis=(-1.0, 0.0, 0.0)), 5.4708, 4.5214)),
            (3, 4, circle_curve(frame((21.3328513, 19.0, 206.7968), z_axis=(0.0, -1.0, 0.0), x_axis=(0.0, 0.0, -1.0)), 3.6518634)),
            (4, 5, circle_curve(frame((23.0562825, 19.0, 209.2784), z_axis=(0.0, -1.0, 0.0), x_axis=(0.0, 0.0, -1.0)), 6.5915864)),
            (5, 6),
            (6, 7, circle_curve(frame((23.8602941, 19.0, 206.402), z_axis=(0.0, 1.0, 0.0), x_axis=(0.0, 0.0, -1.0)), 1.981026)),
            (7, 0, circle_curve(frame((23.4008, 19.0, 205.5278), z_axis=(0.0, 1.0, 0.0), x_axis=(0.0, 0.0, -1.0)), 1.0528)),
            (8, 9),
            (9, 10, circle_curve(frame((23.1517, 19.0, 208.705), z_axis=(0.0, 1.0, 0.0), x_axis=(0.0, 0.0, -1.0)), 0.8037)),
            (10, 11),
            (11, 8),
            (12, 13, circle_curve(frame((23.4008, 20.0, 205.5278), z_axis=(0.0, -1.0, 0.0), x_axis=(0.0, 0.0, -1.0)), 1.0528)),
            (13, 14, circle_curve(frame((23.8602941, 20.0, 206.402), z_axis=(0.0, -1.0, 0.0), x_axis=(0.0, 0.0, -1.0)), 1.981026)),
            (14, 15),
            (15, 16, circle_curve(frame((23.0562825, 20.0, 209.2784), z_axis=(0.0, 1.0, 0.0), x_axis=(0.0, 0.0, -1.0)), 6.5915864)),
            (16, 17, circle_curve(frame((21.3328513, 20.0, 206.7968), z_axis=(0.0, 1.0, 0.0), x_axis=(0.0, 0.0, -1.0)), 3.6518634)),
            (17, 18, ellipse_curve(frame((23.1658, 20.0, 206.4772), z_axis=(0.0, 1.0, 0.0), x_axis=(-1.0, 0.0, 0.0)), 5.4708, 4.5214)),
            (18, 19),
            (19, 12),
            (20, 21),
            (21, 22),
            (22, 23, circle_curve(frame((23.1517, 20.0, 208.705), z_axis=(0.0, -1.0, 0.0), x_axis=(0.0, 0.0, -1.0)), 0.8037)),
            (23, 20),
            (0, 12),
            (19, 1),
            (18, 2),
            (5, 15),
            (14, 6),
            (17, 3),
            (13, 7),
            (16, 4),
            (8, 20),
            (23, 9),
            (22, 10),
            (21, 11),
        ],
        [
            plane_surface(frame((22.348, 19.0, 206.4772), z_axis=(0.0, -1.0, 0.0), x_axis=(0.0, 0.0, 1.0))),
            plane_surface(frame((22.348, 20.0, 206.4772), z_axis=(0.0, 1.0, 0.0), x_axis=(0.0, 0.0, -1.0))),
            plane_surface(frame((22.348, 19.0, 205.5278), z_axis=(1.0, 0.0, 0.0), x_axis=(0.0, 1.0, 0.0))),
            plane_surface(frame((22.348, 19.0, 206.4772), z_axis=(0.0, 0.0, -1.0), x_axis=(0.0, 1.0, 0.0))),
            plane_surface(frame((28.4768, 19.0, 205.5278), z_axis=(0.0, 0.0, 1.0), x_axis=(0.0, 1.0, 0.0))),
            extruded_surface(trimmed(ellipse_curve(frame((23.1658, 21.0, 206.4772), z_axis=(0.0, -1.0, 0.0), x_axis=(-1.0, 0.0, 0.0)), 5.4708, 4.5214), [point((28.6366, 21.0, 206.4772))], [point((17.695, 21.0, 206.4772))], True, "CARTESIAN"), (0.0, -1.0, 0.0), 1.0),
            revolved_surface(polyline([(23.8602941, 20.0, 204.420974), (23.8602941, 19.0, 204.420974)]), (23.8602941, 20.0, 206.402), (0.0, 1.0, 0.0)),
            revolved_surface(polyline([(23.4008, 20.0, 204.47500000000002), (23.4008, 19.0, 204.47500000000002)]), (23.4008, 20.0, 205.5278), (0.0, 1.0, 0.0)),
            cylinder_surface(frame((21.3328513, 20.0, 206.7968), z_axis=(0.0, -1.0, 0.0), x_axis=(0.0, 0.0, -1.0)), 3.6518634),
            cylinder_surface(frame((23.0562825, 20.0, 209.2784), z_axis=(0.0, -1.0, 0.0), x_axis=(0.0, 0.0, -1.0)), 6.5915864),
            plane_surface(frame((22.348, 19.0, 207.6804), z_axis=(1.0, 0.0, 0.0), x_axis=(0.0, 1.0, 0.0))),
            revolved_surface(polyline([(23.1517, 20.0, 207.90130000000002), (23.1517, 19.0, 207.90130000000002)]), (23.1517, 20.0, 208.705), (0.0, 1.0, 0.0)),
            plane_surface(frame((23.9554, 19.0, 208.705), z_axis=(-1.0, 0.0, 0.0), x_axis=(0.0, 1.0, 0.0))),
            plane_surface(frame((23.9554, 19.0, 207.6804), z_axis=(0.0, 0.0, 1.0), x_axis=(0.0, 1.0, 0.0))),
        ],
        [
            (0, [[1, 2, 3, 4, 5, 6, 7, 8], [9, 10, 11, 12]]),
            (1, [[13, 14, 15, 16, 17, 18, 19, 20], [21, 22, 23, 24]]),
            (2, [[-1, 25, -20, 26]]),
            (3, [[-2, -26, -19, 27]]),
            (4, [[-6, 28, -15, 29]]),
            (5, [[-3, -27, -18, 30]]),
            (6, [[-7, -29, -14, 31]]),
            (7, [[-8, -31, -13, -25]]),
            (8, [[-4, -30, -17, 32]]),
            (9, [[-5, -32, -16, -28]]),
            (10, [[-9, 33, -24, 34]]),
            (11, [[-10, -34, -23, 35]]),
            (12, [[-11, -35, -22, 36]]),
            (13, [[-12, -36, -21, -33]]),
        ],
    ),
        advanced_brep(
        [(2.7302, 19.0, 205.5278), (2.7302, 19.0, 206.4772), (9.0188, 19.0, 206.4772), (-1.9228, 19.0, 206.4772), (0.6622, 19.0, 203.3), (8.859, 19.0, 205.5278), (6.0202, 19.0, 205.5278), (3.783, 19.0, 204.475), (2.7302, 19.0, 207.6804), (2.7302, 19.0, 208.705), (4.3376, 19.0, 208.705), (4.3376, 19.0, 207.6804), (2.7302, 20.0, 205.5278), (3.783, 20.0, 204.475), (6.0202, 20.0, 205.5278), (8.859, 20.0, 205.5278), (0.6622, 20.0, 203.3), (-1.9228, 20.0, 206.4772), (9.0188, 20.0, 206.4772), (2.7302, 20.0, 206.4772), (2.7302, 20.0, 207.6804), (4.3376, 20.0, 207.6804), (4.3376, 20.0, 208.705), (2.7302, 20.0, 208.705)],
        [
            (0, 1),
            (1, 2),
            (2, 3, ellipse_curve(frame((3.548, 19.0, 206.4772), z_axis=(0.0, -1.0, 0.0), x_axis=(-1.0, 0.0, 0.0)), 5.4708, 4.5214)),
            (3, 4, circle_curve(frame((1.7150513, 19.0, 206.7968), z_axis=(0.0, -1.0, 0.0), x_axis=(0.0, 0.0, -1.0)), 3.6518634)),
            (4, 5, circle_curve(frame((3.4384825, 19.0, 209.2784), z_axis=(0.0, -1.0, 0.0), x_axis=(0.0, 0.0, -1.0)), 6.5915864)),
            (5, 6),
            (6, 7, circle_curve(frame((4.2424941, 19.0, 206.402), z_axis=(0.0, 1.0, 0.0), x_axis=(0.0, 0.0, -1.0)), 1.981026)),
            (7, 0, circle_curve(frame((3.783, 19.0, 205.5278), z_axis=(0.0, 1.0, 0.0), x_axis=(0.0, 0.0, -1.0)), 1.0528)),
            (8, 9),
            (9, 10, circle_curve(frame((3.5339, 19.0, 208.705), z_axis=(0.0, 1.0, 0.0), x_axis=(0.0, 0.0, -1.0)), 0.8037)),
            (10, 11),
            (11, 8),
            (12, 13, circle_curve(frame((3.783, 20.0, 205.5278), z_axis=(0.0, -1.0, 0.0), x_axis=(0.0, 0.0, -1.0)), 1.0528)),
            (13, 14, circle_curve(frame((4.2424941, 20.0, 206.402), z_axis=(0.0, -1.0, 0.0), x_axis=(0.0, 0.0, -1.0)), 1.981026)),
            (14, 15),
            (15, 16, circle_curve(frame((3.4384825, 20.0, 209.2784), z_axis=(0.0, 1.0, 0.0), x_axis=(0.0, 0.0, -1.0)), 6.5915864)),
            (16, 17, circle_curve(frame((1.7150513, 20.0, 206.7968), z_axis=(0.0, 1.0, 0.0), x_axis=(0.0, 0.0, -1.0)), 3.6518634)),
            (17, 18, ellipse_curve(frame((3.548, 20.0, 206.4772), z_axis=(0.0, 1.0, 0.0), x_axis=(-1.0, 0.0, 0.0)), 5.4708, 4.5214)),
            (18, 19),
            (19, 12),
            (20, 21),
            (21, 22),
            (22, 23, circle_curve(frame((3.5339, 20.0, 208.705), z_axis=(0.0, -1.0, 0.0), x_axis=(0.0, 0.0, -1.0)), 0.8037)),
            (23, 20),
            (0, 12),
            (19, 1),
            (18, 2),
            (5, 15),
            (14, 6),
            (17, 3),
            (13, 7),
            (16, 4),
            (8, 20),
            (23, 9),
            (22, 10),
            (21, 11),
        ],
        [
            plane_surface(frame((2.7302, 19.0, 206.4772), z_axis=(0.0, -1.0, 0.0), x_axis=(0.0, 0.0, 1.0))),
            plane_surface(frame((2.7302, 20.0, 206.4772), z_axis=(0.0, 1.0, 0.0), x_axis=(0.0, 0.0, -1.0))),
            plane_surface(frame((2.7302, 19.0, 205.5278), z_axis=(1.0, 0.0, 0.0), x_axis=(0.0, 1.0, 0.0))),
            plane_surface(frame((2.7302, 19.0, 206.4772), z_axis=(0.0, 0.0, -1.0), x_axis=(0.0, 1.0, 0.0))),
            plane_surface(frame((8.859, 19.0, 205.5278), z_axis=(0.0, 0.0, 1.0), x_axis=(0.0, 1.0, 0.0))),
            extruded_surface(trimmed(ellipse_curve(frame((3.548, 21.0, 206.4772), z_axis=(0.0, -1.0, 0.0), x_axis=(-1.0, 0.0, 0.0)), 5.4708, 4.5214), [point((9.0188, 21.0, 206.4772))], [point((-1.9228, 21.0, 206.4772))], True, "CARTESIAN"), (0.0, -1.0, 0.0), 1.0),
            revolved_surface(polyline([(4.2424941, 20.0, 204.420974), (4.2424941, 19.0, 204.420974)]), (4.2424941, 20.0, 206.402), (0.0, 1.0, 0.0)),
            revolved_surface(polyline([(3.783, 20.0, 204.47500000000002), (3.783, 19.0, 204.47500000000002)]), (3.783, 20.0, 205.5278), (0.0, 1.0, 0.0)),
            cylinder_surface(frame((1.7150513, 20.0, 206.7968), z_axis=(0.0, -1.0, 0.0), x_axis=(0.0, 0.0, -1.0)), 3.6518634),
            cylinder_surface(frame((3.4384825, 20.0, 209.2784), z_axis=(0.0, -1.0, 0.0), x_axis=(0.0, 0.0, -1.0)), 6.5915864),
            plane_surface(frame((2.7302, 19.0, 207.6804), z_axis=(1.0, 0.0, 0.0), x_axis=(0.0, 1.0, 0.0))),
            revolved_surface(polyline([(3.5339, 20.0, 207.90130000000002), (3.5339, 19.0, 207.90130000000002)]), (3.5339, 20.0, 208.705), (0.0, 1.0, 0.0)),
            plane_surface(frame((4.3376, 19.0, 208.705), z_axis=(-1.0, 0.0, 0.0), x_axis=(0.0, 1.0, 0.0))),
            plane_surface(frame((4.3376, 19.0, 207.6804), z_axis=(0.0, 0.0, 1.0), x_axis=(0.0, 1.0, 0.0))),
        ],
        [
            (0, [[1, 2, 3, 4, 5, 6, 7, 8], [9, 10, 11, 12]]),
            (1, [[13, 14, 15, 16, 17, 18, 19, 20], [21, 22, 23, 24]]),
            (2, [[-1, 25, -20, 26]]),
            (3, [[-2, -26, -19, 27]]),
            (4, [[-6, 28, -15, 29]]),
            (5, [[-3, -27, -18, 30]]),
            (6, [[-7, -29, -14, 31]]),
            (7, [[-8, -31, -13, -25]]),
            (8, [[-4, -30, -17, 32]]),
            (9, [[-5, -32, -16, -28]]),
            (10, [[-9, 33, -24, 34]]),
            (11, [[-10, -34, -23, 35]]),
            (12, [[-11, -35, -22, 36]]),
            (13, [[-12, -36, -21, -33]]),
        ],
    ),
        extrude(outline(polyline([(212.1454, -7.544), (210.6226, -6.8296), (212.1078, -3.643), (213.6306, -4.348), (212.1454, -7.544)])), frame((0.0, 19.0, 0.0), z_axis=(0.0, 1.0, 0.0), x_axis=(0.0, 0.0, 1.0)), (0.0, 0.0, 1.0), 1.0),
        extrude(outline(polyline([(210.4158, -9.8658), (208.7332, -9.8658), (208.7332, -8.7472), (204.8792, -8.7472), (204.8792, -9.8658), (203.3, -9.8658), (203.3, -2.4492), (204.8792, -2.4492), (204.8792, -3.5396), (210.4158, -3.5396), (210.4158, -9.8658)])), frame((0.0, 19.0, 0.0), z_axis=(0.0, 1.0, 0.0), x_axis=(0.0, 0.0, 1.0)), (0.0, 0.0, 1.0), 1.0),
        extrude(outline(polyline([(211.1678, 9.5452), (211.1678, 10.6732), (204.8792, 10.6732), (204.8792, 9.5452), (203.3, 9.5452), (203.3, 17.1686), (204.8792, 17.1686), (204.8792, 16.0124), (212.7, 16.0124), (212.7, 9.5452), (211.1678, 9.5452)])), frame((0.0, 19.0, 0.0), z_axis=(0.0, 1.0, 0.0), x_axis=(0.0, 0.0, 1.0)), (0.0, 0.0, 1.0), 1.0),
        extrude(outline(polyline([(211.1678, -28.6), (211.1678, -27.4626), (204.8792, -27.4626), (204.8792, -28.6), (203.3, -28.6), (203.3, -24.464), (204.8792, -24.464), (204.8792, -25.592), (208.8689247, -25.592), (203.3, -21.3902), (208.9902223, -17.1696), (204.8792, -17.1696), (204.8792, -18.3258), (203.3, -18.3258), (203.3, -10.8246), (204.8792, -10.8246), (204.8792, -12.0184), (211.1678, -12.0184), (211.1678, -10.8246), (212.7, -10.8246), (212.7, -16.5492), (209.175, -19.294), (212.7, -22.0482), (212.7, -28.6), (211.1678, -28.6)])), frame((0.0, 19.0, 0.0), z_axis=(0.0, 1.0, 0.0), x_axis=(0.0, 0.0, 1.0)), (0.0, 0.0, 1.0), 1.0),
        extrude(outline(polyline([(337.0, 297.5), (337.0, -297.5), (4.0, -297.5), (4.0, 297.5), (337.0, 297.5)]), holes=[polyline([(272.0, 237.5), (64.0, 237.5), (64.0, -237.5), (272.0, -237.5), (272.0, 237.5)])]), frame((0.0, -18.0, 0.0), z_axis=(0.0, 1.0, 0.0), x_axis=(0.0, 0.0, 1.0)), (0.0, 0.0, 1.0), 5.0),
        extrude(outline(polyline([(-297.5, -18.0), (-237.5, -18.0), (-237.5, -22.0), (-297.5, -22.0), (-297.5, -18.0)])), frame((0.0, 0.0, 64.5), z_axis=(0.0, 0.0, 1.0), x_axis=(1.0, 0.0, 0.0)), (0.0, 0.0, 1.0), 207.0),
        extrude(outline(polyline([(237.5, -18.0), (297.5, -18.0), (297.5, -22.0), (237.5, -22.0), (237.5, -18.0)])), frame((0.0, 0.0, 64.5), z_axis=(0.0, 0.0, 1.0), x_axis=(1.0, 0.0, 0.0)), (0.0, 0.0, 1.0), 207.0),
        extrude(outline(polyline([(-297.5, -18.0), (297.5, -18.0), (297.5, -22.0), (-297.5, -22.0), (-297.5, -18.0)])), frame((0.0, 0.0, 272.0), z_axis=(0.0, 0.0, 1.0), x_axis=(1.0, 0.0, 0.0)), (0.0, 0.0, 1.0), 65.0),
        extrude(outline(polyline([(-297.5, -18.0), (297.5, -18.0), (297.5, -22.0), (-297.5, -22.0), (-297.5, -18.0)])), frame((0.0, 0.0, 4.0), z_axis=(0.0, 0.0, 1.0), x_axis=(1.0, 0.0, 0.0)), (0.0, 0.0, 1.0), 60.0),
        extrude(outline(polyline([(297.5, -22.0), (-297.5, -22.0), (-297.5, -13.0), (297.5, -13.0), (297.5, -22.0)])), frame((0.0, 0.0, 344.0), z_axis=(0.0, 0.0, 1.0), x_axis=(1.0, 0.0, 0.0)), (0.0, 0.0, 1.0), 111.5),
        extrude(outline(composite_curve([segment(trimmed(circle_curve(frame_2d((361.0, -140.5745637)), 6.0), [point((361.0, -146.5745637))], [point((361.0, -134.5745637))], False, "CARTESIAN"), True, "CONTINUOUS"), segment(trimmed(circle_curve(frame_2d((361.0, -140.5745637)), 6.0), [point((361.0, -134.5745637))], [point((361.0, -146.5745637))], False, "CARTESIAN"), True, "CONTINUOUS")], self_intersect=False)), frame((0.0, -22.5, 0.0), z_axis=(0.0, 1.0, 0.0), x_axis=(0.0, 0.0, 1.0)), (0.0, 0.0, 1.0), 1.0),
    ])


if __name__ == "__main__":
    model = new_model("IFC4")
    model_context = context("Model", 3, world=origin())
    ifc_project = project(units=[si_unit("LENGTHUNIT", "METRE", prefix="MILLI")], contexts=[model_context])
    site = spatial("IfcSite", under=ifc_project)
    building = spatial("IfcBuilding", under=site)
    placement = place(None, origin())
    specialty_equipment_shape = specialty_equipment_e3dbea78(model_context)
    element("IfcBuildingElementProxy", 1, Name="Specialty Equipment", at=placement, inside=building, context=model_context, shape_type="MappedRepresentation", body=[
        mapped(specialty_equipment_shape, transform((0.0, 0.0, 0.0), x_axis=(1.0, 0.0, 0.0), y_axis=(0.0, 1.0, 0.0), z_axis=(0.0, 0.0, 1.0))),
    ])
    save(model, "model.ifc")
